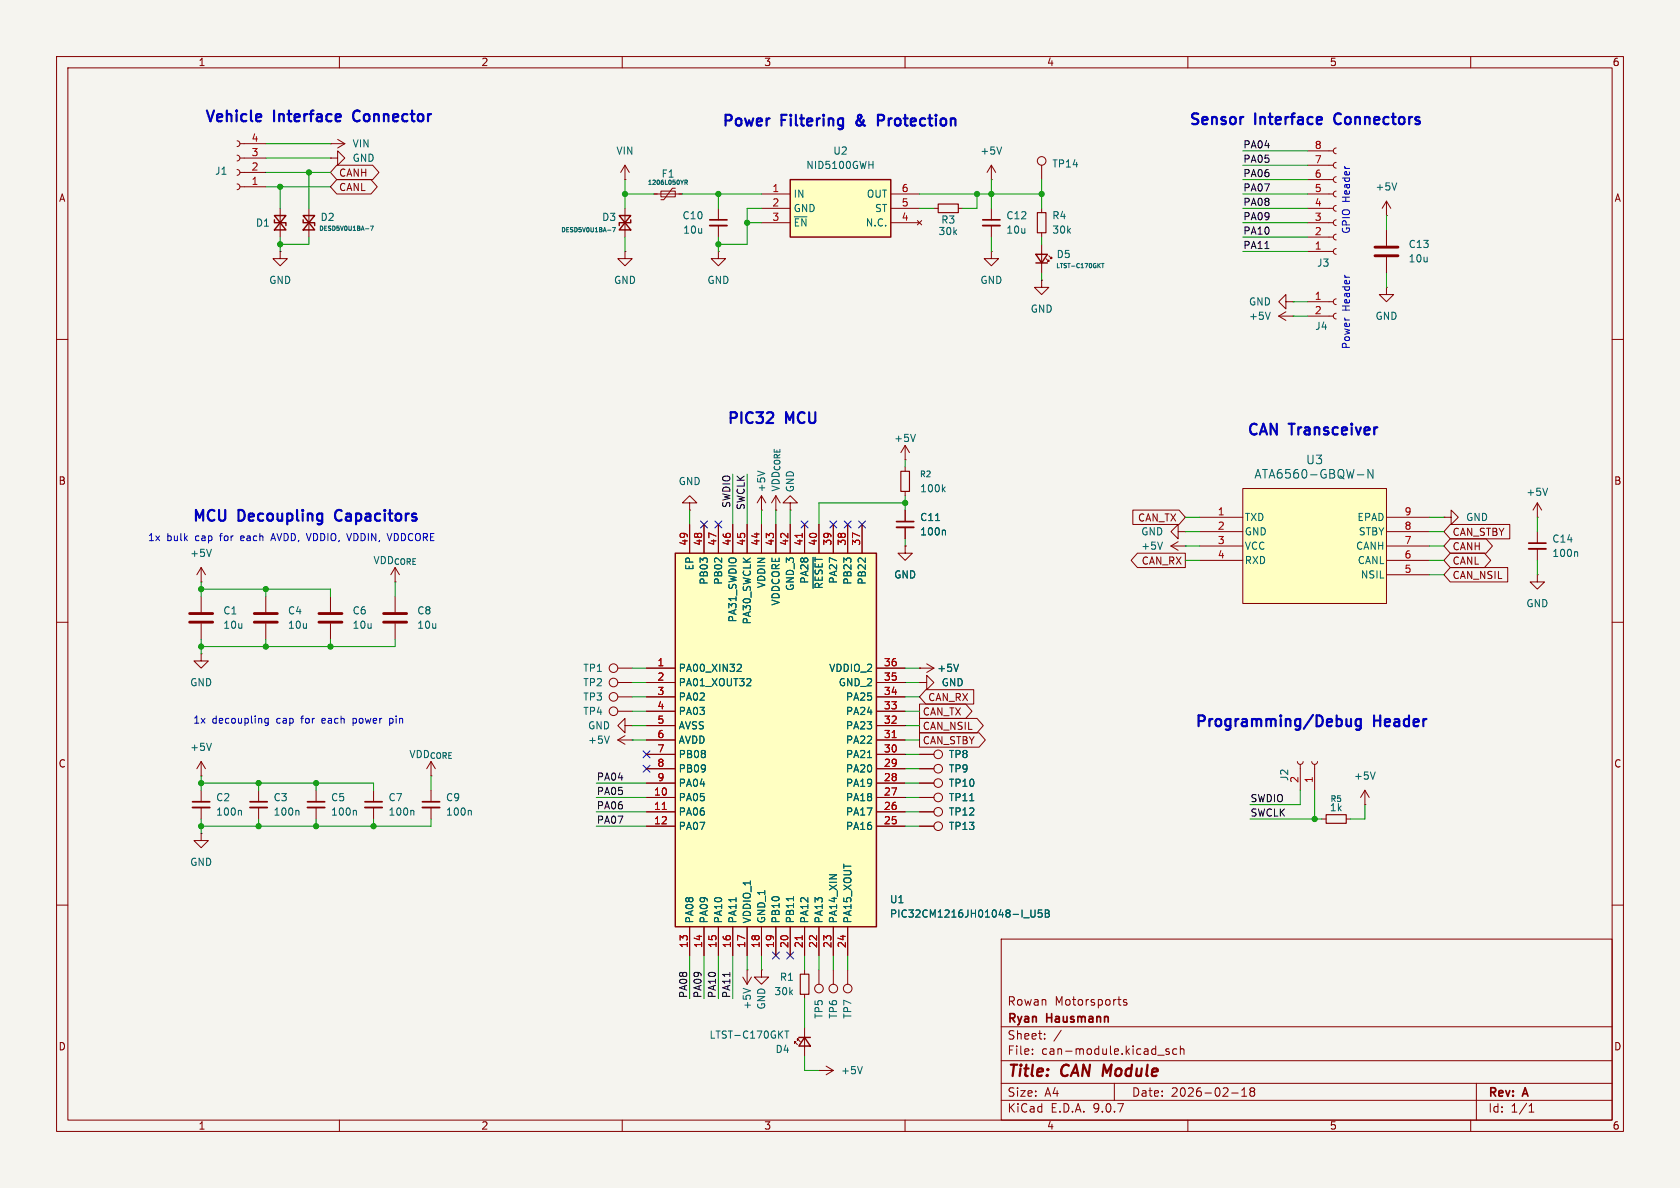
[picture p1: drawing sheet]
<svg xmlns="http://www.w3.org/2000/svg" width="297mm" height="210mm" viewBox="0 0 297 210" stroke-linecap="round" stroke-linejoin="round" font-family="sans-serif">
<defs><g id="words">
<g font-size="2.8" fill="#840000">
<text x="178" y="190.9">Title:</text>
<text x="187.7" y="190.9">CAN Module</text>
</g>
<g font-size="2.7" fill="#0000c2">
<text x="36" y="22.1">Vehicle</text>
<text x="48.4" y="22.1">Interface</text>
<text x="63.2" y="22.1">Connector</text>
<text x="127.4" y="22.9">Power</text>
<text x="138.1" y="22.9">Filtering</text>
<text x="152.1" y="22.9">&amp;</text>
<text x="156.7" y="22.9">Protection</text>
<text x="210" y="22.6">Sensor</text>
<text x="221.8" y="22.6">Interface</text>
<text x="236.7" y="22.6">Connectors</text>
<text x="128.3" y="75.4">PIC32</text>
<text x="138.9" y="75.4">MCU</text>
<text x="220.3" y="77.5">CAN</text>
<text x="228" y="77.5">Transceiver</text>
<text x="33.8" y="92.7">MCU</text>
<text x="42.1" y="92.7">Decoupling</text>
<text x="60" y="92.7">Capacitors</text>
<text x="211.1" y="129">Programming/Debug</text>
<text x="242.9" y="129">Header</text>
</g>
<g font-size="2.1" fill="#006464">
<text x="230.8" y="82.3">U3</text>
<text x="221.7" y="84.8">ATA6560-GBQW-N</text>
</g>
<g font-size="2.1" fill="#840000">
<text x="178" y="178">Rowan</text>
<text x="186.4" y="178">Motorsports</text>
<text x="178" y="184">Sheet:</text>
<text x="178" y="181.2">Ryan</text>
<text x="185.1" y="181.2">Hausmann</text>
<text x="178" y="186.7">File:</text>
<text x="184.1" y="186.7">can-module.kicad_sch</text>
<text x="178" y="196.9">KiCad</text>
<text x="178" y="194.1">Size:</text>
<text x="184.7" y="194.1">A4</text>
<text x="185.7" y="196.9">E.D.A.</text>
<text x="193.3" y="196.9">9.0.7</text>
<text x="200" y="194.1">Date:</text>
<text x="207" y="194.1">2026-02-18</text>
<text x="263" y="194.3">Rev:</text>
<text x="263" y="196.9">Id:</text>
<text x="267.1" y="196.9">1/1</text>
<text x="269.4" y="194.3">A</text>
</g>
<g font-size="1.8" fill="#840000">
<text x="35" y="11.9">1</text>
<text x="85" y="11.9">2</text>
<text x="135" y="11.9">3</text>
<text x="185" y="11.9">4</text>
<text x="235" y="11.9">5</text>
<text x="285" y="11.9">6</text>
<text x="10.3" y="35.9">A</text>
<text x="59.8" y="31.4">CANH</text>
<text x="59.8" y="34">CANL</text>
<text x="285.3" y="35.9">A</text>
<text x="10.3" y="85.9">B</text>
<text x="285.3" y="85.9">B</text>
<text x="201.1" y="92.4">CAN_TX</text>
<text x="256.7" y="94.9">CAN_STBY</text>
<text x="201.7" y="100">CAN_RX</text>
<text x="256.7" y="100">CANL</text>
<text x="256.7" y="97.5">CANH</text>
<text x="256.7" y="102.6">CAN_NSIL</text>
<text x="164" y="124.1">CAN_RX</text>
<text x="163" y="131.8">CAN_STBY</text>
<text x="163" y="129.2">CAN_NSIL</text>
<text x="163" y="126.7">CAN_TX</text>
<text x="10.3" y="135.9">C</text>
<text x="285.3" y="135.9">C</text>
<text x="10.3" y="185.9">D</text>
<text x="285.3" y="185.9">D</text>
<text x="35" y="199.9">1</text>
<text x="85" y="199.9">2</text>
<text x="135" y="199.9">3</text>
<text x="185" y="199.9">4</text>
<text x="235" y="199.9">5</text>
<text x="285" y="199.9">6</text>
</g>
<g font-size="1.8" fill="#a90000">
<text x="44.4" y="27.7">3</text>
<text x="44.4" y="25.1">4</text>
<text x="232.3" y="29">7</text>
<text x="232.3" y="26.4">8</text>
<text x="44.4" y="32.8">1</text>
<text x="44.4" y="30.2">2</text>
<text x="136.5" y="34">1</text>
<text x="159.3" y="34">6</text>
<text x="232.3" y="34">5</text>
<text x="232.3" y="31.5">6</text>
<text x="136.5" y="36.6">2</text>
<text x="136.5" y="39.1">3</text>
<text x="159.3" y="36.6">5</text>
<text x="159.3" y="39.1">4</text>
<text x="232.3" y="41.7">2</text>
<text x="232.3" y="39.1">3</text>
<text x="232.3" y="36.6">4</text>
<text x="232.3" y="44.2">1</text>
<text x="232.3" y="53.1">1</text>
<text x="232.3" y="55.6">2</text>
<text x="215.2" y="91.2">1</text>
<text x="215.2" y="93.7">2</text>
<text x="248.2" y="91.2">9</text>
<text x="248.2" y="93.7">8</text>
<text x="121.7" y="96.6" transform="rotate(-90 121.7 96.6)">49</text>
<text x="124.2" y="96.6" transform="rotate(-90 124.2 96.6)">48</text>
<text x="126.7" y="96.6" transform="rotate(-90 126.7 96.6)">47</text>
<text x="129.3" y="96.6" transform="rotate(-90 129.3 96.6)">46</text>
<text x="131.8" y="96.6" transform="rotate(-90 131.8 96.6)">45</text>
<text x="134.4" y="96.6" transform="rotate(-90 134.4 96.6)">44</text>
<text x="136.9" y="96.6" transform="rotate(-90 136.9 96.6)">43</text>
<text x="139.4" y="96.6" transform="rotate(-90 139.4 96.6)">42</text>
<text x="142" y="96.6" transform="rotate(-90 142 96.6)">41</text>
<text x="144.5" y="96.6" transform="rotate(-90 144.5 96.6)">40</text>
<text x="147.1" y="96.6" transform="rotate(-90 147.1 96.6)">39</text>
<text x="149.6" y="96.6" transform="rotate(-90 149.6 96.6)">38</text>
<text x="152.1" y="96.6" transform="rotate(-90 152.1 96.6)">37</text>
<text x="215.2" y="96.3">3</text>
<text x="215.2" y="98.8">4</text>
<text x="248.2" y="96.3">7</text>
<text x="248.2" y="98.8">6</text>
<text x="248.2" y="101.3">5</text>
<text x="116.1" y="117.9">1</text>
<text x="156.2" y="117.9">36</text>
<text x="116.1" y="120.4">2</text>
<text x="116.1" y="122.9">3</text>
<text x="116.1" y="125.5">4</text>
<text x="156.2" y="120.4">35</text>
<text x="156.2" y="122.9">34</text>
<text x="156.2" y="125.5">33</text>
<text x="116.1" y="128">5</text>
<text x="116.1" y="130.6">6</text>
<text x="156.2" y="128">32</text>
<text x="156.2" y="130.6">31</text>
<text x="116.1" y="133.1">7</text>
<text x="116.1" y="135.6">8</text>
<text x="156.2" y="133.1">30</text>
<text x="156.2" y="135.6">29</text>
<text x="115.5" y="140.7">10</text>
<text x="115.5" y="143.3">11</text>
<text x="116.1" y="138.2">9</text>
<text x="156.2" y="138.2">28</text>
<text x="156.2" y="140.7">27</text>
<text x="156.2" y="143.3">26</text>
<text x="229.6" y="138.5" transform="rotate(-90 229.6 138.5)">2</text>
<text x="232.2" y="138.5" transform="rotate(-90 232.2 138.5)">1</text>
<text x="115.5" y="145.8">12</text>
<text x="156.2" y="145.8">25</text>
<text x="121.7" y="167.7" transform="rotate(-90 121.7 167.7)">13</text>
<text x="124.2" y="167.7" transform="rotate(-90 124.2 167.7)">14</text>
<text x="126.7" y="167.7" transform="rotate(-90 126.7 167.7)">15</text>
<text x="129.3" y="167.7" transform="rotate(-90 129.3 167.7)">16</text>
<text x="131.8" y="167.7" transform="rotate(-90 131.8 167.7)">17</text>
<text x="134.4" y="167.7" transform="rotate(-90 134.4 167.7)">18</text>
<text x="136.9" y="167.7" transform="rotate(-90 136.9 167.7)">19</text>
<text x="139.4" y="167.7" transform="rotate(-90 139.4 167.7)">20</text>
<text x="142" y="167.7" transform="rotate(-90 142 167.7)">21</text>
<text x="144.5" y="167.7" transform="rotate(-90 144.5 167.7)">22</text>
<text x="147.1" y="167.7" transform="rotate(-90 147.1 167.7)">23</text>
<text x="149.6" y="167.7" transform="rotate(-90 149.6 167.7)">24</text>
</g>
<g font-size="1.8" fill="#006464">
<text x="62.2" y="26.3">VIN</text>
<text x="62.2" y="28.8">GND</text>
<text x="108.9" y="27.5">VIN</text>
<text x="147.2" y="27.5">U2</text>
<text x="173.2" y="27.5">+5V</text>
<text x="185.9" y="29.8">TP14</text>
<text x="37.9" y="31.1">J1</text>
<text x="116.9" y="31.6">F1</text>
<text x="140.2" y="35.2">IN</text>
<text x="142.4" y="30.1">NID5100GWH</text>
<text x="153.1" y="35.2">OUT</text>
<text x="243.1" y="33.9">+5V</text>
<text x="45.1" y="40.3">D1</text>
<text x="56.6" y="39.3">D2</text>
<text x="106.4" y="39.3">D3</text>
<text x="120.6" y="39">C10</text>
<text x="120.7" y="41.5">10u</text>
<text x="140.2" y="37.7">GND</text>
<text x="140.2" y="40.2">~{EN}</text>
<text x="153" y="40.2">N.C.</text>
<text x="154.6" y="37.7">ST</text>
<text x="165.8" y="41.8">30k</text>
<text x="166.3" y="39.7">R3</text>
<text x="177.8" y="39">C12</text>
<text x="177.8" y="41.5">10u</text>
<text x="185.9" y="39">R4</text>
<text x="185.9" y="41.5">30k</text>
<text x="186.7" y="45.8">D5</text>
<text x="232.7" y="47.3">J3</text>
<text x="248.9" y="44">C13</text>
<text x="248.9" y="46.6">10u</text>
<text x="47.5" y="50.4">GND</text>
<text x="108.5" y="50.4">GND</text>
<text x="125" y="50.4">GND</text>
<text x="173.2" y="50.4">GND</text>
<text x="182.1" y="55.5">GND</text>
<text x="220.7" y="54.2">GND</text>
<text x="220.7" y="56.7">+5V</text>
<text x="232.4" y="58.5">J4</text>
<text x="243.1" y="56.7">GND</text>
<text x="158" y="78.3">+5V</text>
<text x="119.9" y="86">GND</text>
<text x="135.5" y="87.1" transform="rotate(-90 135.5 87.1)">+5V</text>
<text x="138" y="87" transform="rotate(-90 138 87)">VDD_{CORE}</text>
<text x="140.6" y="87.1" transform="rotate(-90 140.6 87.1)">GND</text>
<text x="162.6" y="87.2">100k</text>
<text x="269.7" y="87.9">+5V</text>
<text x="162.6" y="94.8">100n</text>
<text x="162.6" y="92.3">C11</text>
<text x="201.7" y="94.8">GND</text>
<text x="220" y="92.3">TXD</text>
<text x="220" y="94.8">GND</text>
<text x="239.9" y="92.3">EPAD</text>
<text x="240.1" y="94.8">STBY</text>
<text x="259.1" y="92.3">GND</text>
<text x="33.5" y="98.7">+5V</text>
<text x="65.9" y="99.9">VDD_{CORE}</text>
<text x="122.8" y="100.9" transform="rotate(-90 122.8 100.9)">EP</text>
<text x="201.7" y="97.4">+5V</text>
<text x="220" y="97.4">VCC</text>
<text x="220" y="99.9">RXD</text>
<text x="239.6" y="97.4">CANH</text>
<text x="239.9" y="99.9">CANL</text>
<text x="274.3" y="98.7">100n</text>
<text x="274.3" y="96.1">C14</text>
<text x="125.3" y="103.5" transform="rotate(-90 125.3 103.5)">PB03</text>
<text x="127.9" y="103.5" transform="rotate(-90 127.9 103.5)">PB02</text>
<text x="135.5" y="104.1" transform="rotate(-90 135.5 104.1)">VDDIN</text>
<text x="138" y="107.1" transform="rotate(-90 138 107.1)">VDDCORE</text>
<text x="140.6" y="104.5" transform="rotate(-90 140.6 104.5)">GND_3</text>
<text x="143.1" y="103.3" transform="rotate(-90 143.1 103.3)">PA28</text>
<text x="145.6" y="104.2" transform="rotate(-90 145.6 104.2)">~{RESET}</text>
<text x="148.2" y="103.3" transform="rotate(-90 148.2 103.3)">PA27</text>
<text x="150.7" y="103.5" transform="rotate(-90 150.7 103.5)">PB23</text>
<text x="153.3" y="103.5" transform="rotate(-90 153.3 103.5)">PB22</text>
<text x="158" y="102.5">GND</text>
<text x="240.5" y="102.5">NSIL</text>
<text x="269.7" y="107.5">GND</text>
<text x="39.4" y="108.8">C1</text>
<text x="39.4" y="111.4">10u</text>
<text x="50.8" y="108.8">C4</text>
<text x="50.8" y="111.4">10u</text>
<text x="62.2" y="108.8">C6</text>
<text x="62.2" y="111.4">10u</text>
<text x="73.7" y="108.8">C8</text>
<text x="73.7" y="111.4">10u</text>
<text x="130.4" y="110.1" transform="rotate(-90 130.4 110.1)">PA31_SWDIO</text>
<text x="132.9" y="110.5" transform="rotate(-90 132.9 110.5)">PA30_SWCLK</text>
<text x="103" y="119">TP1</text>
<text x="119.9" y="119">PA00_XIN32</text>
<text x="146.5" y="119">VDDIO_2</text>
<text x="165.6" y="119">+5V</text>
<text x="33.5" y="121.5">GND</text>
<text x="103" y="121.5">TP2</text>
<text x="103" y="124.1">TP3</text>
<text x="119.9" y="121.5">PA01_XOUT32</text>
<text x="119.9" y="124.1">PA02</text>
<text x="148.2" y="121.5">GND_2</text>
<text x="149.5" y="124.1">PA25</text>
<text x="166.4" y="121.5">GND</text>
<text x="103" y="126.6">TP4</text>
<text x="103.9" y="129.1">GND</text>
<text x="103.9" y="131.7">+5V</text>
<text x="119.9" y="126.6">PA03</text>
<text x="119.9" y="129.1">AVSS</text>
<text x="119.9" y="131.7">AVDD</text>
<text x="149.5" y="126.6">PA24</text>
<text x="149.5" y="129.1">PA23</text>
<text x="149.5" y="131.7">PA22</text>
<text x="33.5" y="132.9">+5V</text>
<text x="72.3" y="134.2">VDD_{CORE}</text>
<text x="119.9" y="134.2">PB08</text>
<text x="119.9" y="136.8">PB09</text>
<text x="149.5" y="134.2">PA21</text>
<text x="149.5" y="136.8">PA20</text>
<text x="167.6" y="136.8">TP9</text>
<text x="167.6" y="134.2">TP8</text>
<text x="38.1" y="141.8">C2</text>
<text x="48.3" y="141.8">C3</text>
<text x="58.4" y="141.8">C5</text>
<text x="68.6" y="141.8">C7</text>
<text x="78.7" y="141.8">C9</text>
<text x="119.9" y="139.3">PA04</text>
<text x="119.9" y="141.8">PA05</text>
<text x="149.5" y="139.3">PA19</text>
<text x="149.5" y="141.8">PA18</text>
<text x="167.6" y="141.8">TP11</text>
<text x="167.6" y="139.3">TP10</text>
<text x="227.9" y="138.2" transform="rotate(-90 227.9 138.2)">J2</text>
<text x="235" y="143.6">1k</text>
<text x="239.3" y="138">+5V</text>
<text x="38.1" y="144.4">100n</text>
<text x="48.3" y="144.4">100n</text>
<text x="58.4" y="144.4">100n</text>
<text x="68.6" y="144.4">100n</text>
<text x="78.7" y="144.4">100n</text>
<text x="119.9" y="144.4">PA06</text>
<text x="119.9" y="146.9">PA07</text>
<text x="149.5" y="144.4">PA17</text>
<text x="149.5" y="146.9">PA16</text>
<text x="167.6" y="146.9">TP13</text>
<text x="167.6" y="144.4">TP12</text>
<text x="33.5" y="153.3">GND</text>
<text x="157.2" y="159.9">U1</text>
<text x="122.8" y="163.3" transform="rotate(-90 122.8 163.3)">PA08</text>
<text x="125.3" y="163.3" transform="rotate(-90 125.3 163.3)">PA09</text>
<text x="127.9" y="163.3" transform="rotate(-90 127.9 163.3)">PA10</text>
<text x="130.4" y="163.3" transform="rotate(-90 130.4 163.3)">PA11</text>
<text x="132.9" y="163.3" transform="rotate(-90 132.9 163.3)">VDDIO_1</text>
<text x="135.5" y="163.3" transform="rotate(-90 135.5 163.3)">GND_1</text>
<text x="138" y="163.3" transform="rotate(-90 138 163.3)">PB10</text>
<text x="140.6" y="163.3" transform="rotate(-90 140.6 163.3)">PB11</text>
<text x="143.1" y="163.3" transform="rotate(-90 143.1 163.3)">PA12</text>
<text x="145.6" y="163.3" transform="rotate(-90 145.6 163.3)">PA13</text>
<text x="148.2" y="163.3" transform="rotate(-90 148.2 163.3)">PA14_XIN</text>
<text x="150.7" y="163.3" transform="rotate(-90 150.7 163.3)">PA15_XOUT</text>
<text x="157.2" y="162.4">PIC32CM1216JH01048-I_U5B</text>
<text x="137.8" y="173.6">R1</text>
<text x="132.9" y="178.6" transform="rotate(-90 132.9 178.6)">+5V</text>
<text x="135.5" y="178.6" transform="rotate(-90 135.5 178.6)">GND</text>
<text x="136.8" y="176.1">30k</text>
<text x="125.3" y="183.8">LTST-C170GKT</text>
<text x="145.6" y="180.2" transform="rotate(-90 145.6 180.2)">TP5</text>
<text x="148.2" y="180.2" transform="rotate(-90 148.2 180.2)">TP6</text>
<text x="150.7" y="180.2" transform="rotate(-90 150.7 180.2)">TP7</text>
<text x="137" y="186.3">D4</text>
<text x="148.6" y="190.1">+5V</text>
</g>
<g font-size="1.8" fill="#0f0f0f">
<text x="219.7" y="26.3">PA04</text>
<text x="219.7" y="28.9">PA05</text>
<text x="219.7" y="31.4">PA06</text>
<text x="219.7" y="33.9">PA07</text>
<text x="219.7" y="41.6">PA10</text>
<text x="219.7" y="39">PA09</text>
<text x="219.7" y="36.5">PA08</text>
<text x="219.7" y="44.1">PA11</text>
<text x="129.2" y="89.9" transform="rotate(-90 129.2 89.9)">SWDIO</text>
<text x="131.7" y="90.3" transform="rotate(-90 131.7 90.3)">SWCLK</text>
<text x="105.4" y="140.6">PA05</text>
<text x="105.4" y="138.1">PA04</text>
<text x="105.4" y="143.2">PA06</text>
<text x="221" y="141.9">SWDIO</text>
<text x="105.4" y="145.7">PA07</text>
<text x="221" y="144.4">SWCLK</text>
<text x="121.6" y="176.5" transform="rotate(-90 121.6 176.5)">PA08</text>
<text x="124.1" y="176.5" transform="rotate(-90 124.1 176.5)">PA09</text>
<text x="126.7" y="176.5" transform="rotate(-90 126.7 176.5)">PA10</text>
<text x="129.2" y="176.5" transform="rotate(-90 129.2 176.5)">PA11</text>
</g>
<g font-size="1.8" fill="#0000c2">
<text x="238.9" y="35.8" transform="rotate(-90 238.9 35.8)">Header</text>
<text x="238.9" y="41.4" transform="rotate(-90 238.9 41.4)">GPIO</text>
<text x="238.9" y="55" transform="rotate(-90 238.9 55)">Header</text>
<text x="238.9" y="61.8" transform="rotate(-90 238.9 61.8)">Power</text>
<text x="26.1" y="95.9">1x</text>
<text x="29.5" y="95.9">bulk</text>
<text x="34.6" y="95.9">cap</text>
<text x="39.2" y="95.9">for</text>
<text x="43" y="95.9">each</text>
<text x="48.7" y="95.9">AVDD, VDDIO,</text>
<text x="62.5" y="95.9">VDDIN,</text>
<text x="69.8" y="95.9">VDDCORE</text>
<text x="34.1" y="128.1">1x</text>
<text x="37.5" y="128.1">decoupling</text>
<text x="49" y="128.1">cap</text>
<text x="53.6" y="128.1">for</text>
<text x="57.4" y="128.1">each</text>
<text x="63" y="128.1">power</text>
<text x="69.7" y="128.1">pin</text>
</g>
<g font-size="1.4" fill="#006464">
<text x="162.5" y="84.6">R2</text>
<text x="235.1" y="142">R5</text>
</g>
<g font-size="1.1" fill="#006464">
<text x="114.4" y="32.9">1206L050YR</text>
<text x="56.3" y="41">DESD5V0U1BA-7</text>
<text x="99.1" y="41.2">DESD5V0U1BA-7</text>
<text x="186.6" y="47.6">LTST-C170GKT</text>
</g>
</g></defs>
<path d="M0 0h297v210h-297z" fill="#f5f4ef" stroke="#f5f4ef" stroke-width=".18"/>
<g fill="none" stroke="#840000" stroke-width=".18">
<path d="M10 10h277v190h-277zM12 12h273v186h-273zM60 10v2M110 10v2M160 10v2M210 10v2M260 10v2M110.5 31.8h.1M110.5 29.2l-.8 1.3M110.5 29.2l.8 1.3M110.5 29.2v2.6M110.5 36.8v5.1"/>
<path d="M10 60h2M285 60h2M160 96.5v1.3h1.3l-1.3 1.3-1.3-1.3h1.3M160 96.5h.1M10 110h2M35.6 115.6v1.2h1.2l-1.2 1.3-1.3-1.3h1.3M35.6 115.6h.1M35.6 105.4v2.8M35.6 110.2v2.8M47 105.4v2.8M47 110.2v2.8M58.4 105.4v2.8"/>
<path d="M58.4 110.2v2.8M69.8 105.4v2.8M69.8 110.2v2.8M162.6 118.1h.1M162.6 118.1h2.5M163.8 117.3l1.3 .8M165.1 118.1l-1.3 .8M285 110h2M35.6 137.2h.1M35.6 134.6v2.6M35.6 134.6l-.8 1.3M35.6 134.6l.7 1.3"/>
<path d="M66 139.7v2M76.2 137.2h.1M76.2 134.6v2.6M76.2 139.7v2M76.2 134.6l-.8 1.3M76.2 134.6l.8 1.3M162.6 120.7h1.2v-1.3l1.3 1.3-1.3 1.2v-1.2M162.6 120.7h.1M162.6 138.4h2.5M162.6 135.9h2.5M66 142.7v2.1M76.2 142.7v2.1"/>
<path d="M162.6 141h2.5M10 160h2M177 166h108v32h-108zM197.6 176.7h.6M198 177.7h.2M199.2 176.8l-.4-.1-.2 .2 .1 .2 .5 .2v.3h-.6M285 160h2M60 198v2M110 198v2M160 198v2M177 194.5h108M177 191.5h108"/>
<path d="M177 187.5h108M177 181.5h108M182.5 186.3v.1M182.5 185.5v.1M184.7 183.6v.1M184.7 182.8v.1M187.6 182.1l-1.3 2M197 191.5v3M204.7 186.5h1.1M206.7 185.5l-.4-.1-.2 .2 .1 .2 .5 .2v.3h-.6M208 185.5l-.4-.1-.3 .3v.4l.2 .2h.5M208.7 185.5l.2-.1 .3 .1 .1 .9"/>
<path d="M208.7 184.9v1.5M210 198v2M217.7 193.2h1.2M219.5 193.8h.9M219.5 192.7l.5-.4v1.5M221.2 192.9l-.2 .3v.5l.2 .1 .5-.1 .1-.2-.1-.4-.2-.2M221.2 192.9l-.2-.2 .2-.4 .5 .1 .1 .2-.3 .3M221.2 192.9h.3M260 198v2M261 191.5v6.5M270.3 196.6h.9M270.3 195.5l.4-.4v1.5"/>
<circle cx="165.9" cy="135.9" r=".76"/>
<circle cx="165.9" cy="138.4" r=".76"/>
<circle cx="165.9" cy="141" r=".76"/>
</g>
<path d="M33.5 108.5h4.1M33.5 110h4.1M45 108.5h4M45 110h4M56.4 108.5h4.1M56.4 110h4.1M67.8 108.5h4.1M67.8 110h4.1" fill="none" stroke="#840000" stroke-width=".51"/>
<path d="M107.4 40.7h.6M108.3 40.2h.5l-.3 .8M169.5 117.4l-.5 1.3M37.4 131.4l-.4 1.3M73 143.2l.2 .2v.7M83.1 143.2l.2 .2v.7M171.4 141.5h.8" fill="none" stroke="#006464" stroke-width=".18"/>
<path d="M64.5 141.7h3.1M74.7 141.7h3" fill="none" stroke="#840000" stroke-width=".3"/>
<path d="M64.5 142.7h3.1M74.7 142.7h3" fill="none" stroke="#840000" stroke-width=".33"/>
<path d="M109.5 38.1l2 2.5h-2l2-2.5zM111.5 38.9v.5h-2v.5" fill="none" stroke="#840000" stroke-width=".25"/>
<path d="M219.7 86.4h25.4v20.3h-25.4z" fill="#ffffc2"/>
<g fill="none" stroke="#840000" stroke-width=".18">
<path d="M110.5 44.5v1.2h1.3l-1.3 1.3-1.3-1.3h1.3M110.5 44.5h.1M160 78.7v2.6M160 78.7l-.7 1.3M160 78.7l.8 1.3M160 81.3h.1M160 82.6v.7M160 86.9v.7M160 90.2v2M160 93.2v2.1M207 96.5h2.5M207 96.5l1.3 .8"/>
<path d="M208.3 94v-1.3l-1.3 1.3 1.3 1.3v-1.3h1.2M208.3 95.8l-1.3 .7M209.5 96.5h.1M209.5 94h.1M212.1 91.4h7.6M212.1 94h7.6M212.1 96.5h7.6M212.1 99.1h7.6M219.7 86.4h25.4v20.3h-25.4zM245.1 91.4h7.6M245.1 94h7.6M245.1 96.5h7.6"/>
<path d="M245.1 99.1h7.6M255.3 91.4h1.2v-1.2l1.3 1.2-1.3 1.3v-1.3M255.3 91.4h.1M271.8 91.4h.1M271.8 88.9l-.8 1.3M271.8 88.9l.7 1.3M271.8 88.9v2.5M271.8 94v2M271.8 97v2.1M245.1 101.6h7.6M271.8 101.6v1.3h1.2l-1.2 1.2-1.3-1.2h1.3M271.8 101.6h.1"/>
<path d="M229.4 134.6l.1 .4 .4 .1 .3-.1 .2-.4M229.9 135.1v4.6M231.9 134.6l.2 .4 .3 .1 .4-.1 .1-.4M232.4 135.1v4.6M241.3 139.7l-.8 1.3M241.3 139.7l.8 1.3M241.3 139.7v2.5M162.6 146.1h2.5M162.6 143.5h2.5M233.7 144.8h.7M238 144.8h.8M241.3 142.2h.1"/>
<circle cx="165.9" cy="143.5" r=".76"/>
<circle cx="165.9" cy="146" r=".76"/>
</g>
<path d="M161.8 76.8l-.4 1.2M165.4 92h.7M166.7 86.5l.4 .4M167 93.7l.1 .2v.7M167.1 86.1l-.5 .5M205.5 95.8l-.4 1.3M240 83.9h1.1M242.7 83v1.5l-.9-1.5v1.5M273.6 86.3l-.4 1.3M278.7 97.5l.2 .2v.7M243.1 136.5l-.4 1.2" fill="none" stroke="#006464" stroke-width=".18"/>
<path d="M158.5 92.2h3M270.3 96h3" fill="none" stroke="#840000" stroke-width=".3"/>
<path d="M158.5 93.2h3M270.3 97h3" fill="none" stroke="#840000" stroke-width=".33"/>
<path d="M159.3 83.3h1.5v3.6h-1.5zM234.4 144h3.6v1.5h-3.6z" fill="none" stroke="#840000" stroke-width=".2"/>
<path d="M119.4 97.8h35.5v66h-35.5z" fill="#ffffc2"/>
<path d="M48.5 38.1h2l-2 2.5h2zM48.5 38.9v.5h2v.5M53.6 38.1h2l-2 2.5h2zM53.6 38.9v.5h2v.5M119.4 97.8h35.5v66h-35.5zM141.2 183.4h2.1M142.2 183.4l1.1 1.5h-2.1z" fill="none" stroke="#840000" stroke-width=".25"/>
<g fill="none" stroke="#840000" stroke-width=".18">
<path d="M41.9 32.5l.4 .2 .1 .3-.1 .4-.4 .1M41.9 30l.4 .1 .1 .4-.1 .3-.4 .2M41.9 27.4l.4 .2 .1 .3-.1 .4-.4 .1M41.9 24.9l.4 .1 .1 .4-.1 .4-.4 .1M42.4 25.4h4.6M42.4 33h4.6M42.4 30.5h4.6M42.4 27.9h4.6M49.5 36.8v5.1M54.6 36.8v5.1M58.4 25.4h.1M58.4 27.9h1.3v-1.2l1.3 1.2-1.3 1.3v-1.3"/>
<path d="M58.4 27.9h.1M58.4 25.4h2.6M59.7 24.6l1.3 .8M61 25.4l-1.3 .8M115.6 34.3h5M116.8 33.8h2.6v1h-2.6zM119.4 33.3h-.5l-1.6 2h-.5M127 36.8v2.1M127 39.9v2M184.1 29.2v2.6M245.1 38.1h.1M245.1 35.6l-.8 1.2"/>
<path d="M245.1 35.6l.8 1.2M245.1 35.6v2.5M49.5 44.5v1.2h1.3l-1.3 1.3-1.2-1.3h1.2M49.5 44.5h.1M127 44.5v1.2h1.3l-1.3 1.3-1.3-1.3h1.3M127 44.5h.1M121.9 88.9h1.3l-1.3-1.3-1.3 1.3h1.3v1.3M121.9 90.2h.1M121.9 92.7v5.1M124.5 92.7v5.1M127 92.7v5.1M129.5 92.7v5.1"/>
<path d="M132.1 92.7v5.1M134.6 90.2h.1M134.6 87.6v2.6M134.6 92.7v5.1M134.6 87.6l-.7 1.3M134.6 87.6l.8 1.3M137.2 90.2h.1M137.2 87.6v2.6M137.2 92.7v5.1M137.2 87.6l-.8 1.3M137.2 87.6l.7 1.3M139.7 88.9h1.3l-1.3-1.3-1.3 1.3h1.3v1.3"/>
<path d="M139.7 90.2h.1M139.7 92.7v5.1M142.2 92.7v5.1M144.8 92.7v5.1M147.3 92.7v5.1M149.9 92.7v5.1M152.4 92.7v5.1M35.6 102.9h.1M35.6 100.3l-.8 1.3M35.6 100.3l.7 1.3M35.6 100.3v2.6M69.8 102.9h.1"/>
<path d="M69.8 100.3l-.7 1.3M69.8 100.3l.8 1.3M69.8 100.3v2.6M109.2 118.1h2.6M114.3 118.1h5.1M154.9 118.1h5.1M35.6 139.7v2M45.7 139.7v2M55.9 139.7v2M109.2 120.7h2.6M109.2 123.2h2.6M109.2 125.7h2.6"/>
<path d="M109.2 130.8h2.6M109.2 130.8l1.3 .8M110.5 128.3v-1.3l-1.3 1.3 1.3 1.2v-1.2h1.3M110.5 130l-1.3 .8M111.8 128.3h.1M111.8 130.8h.1M114.3 120.7h5.1M114.3 123.2h5.1M114.3 125.7h5.1M114.3 128.3h5.1M114.3 130.8h5.1M114.3 133.4h5.1"/>
<path d="M114.3 135.9h5.1M114.3 138.4h5.1M154.9 120.7h5.1M154.9 123.2h5.1M154.9 125.7h5.1M154.9 128.3h5.1M154.9 130.8h5.1M154.9 133.4h5.1M154.9 135.9h5.1M154.9 138.4h5.1M162.6 133.4h2.5M35.6 147.3v1.3h1.2l-1.2 1.3-1.3-1.3h1.3"/>
<path d="M35.6 147.3h.1M35.6 142.7v2.1M45.7 142.7v2.1M55.9 142.7v2.1M114.3 141h5.1M114.3 143.5h5.1M114.3 146.1h5.1M154.9 141h5.1M154.9 143.5h5.1M154.9 146.1h5.1M121.9 163.8v5.1M124.5 163.8v5.1"/>
<path d="M127 163.8v5.1M129.5 163.8v5.1M131.3 172.7l.8 1.3M132.1 171.5h.1M132.1 163.8v5.1M132.1 171.5v2.5M132.8 172.7l-.7 1.3M134.6 171.5v1.2h1.3l-1.3 1.3-1.3-1.3h1.3M134.6 171.5h.1M134.6 163.8v5.1M137.2 163.8v5.1M139.7 163.8v5.1"/>
<path d="M142.2 163.8v5.1M142.2 171.5v.7M142.2 175.8v.7M144.8 163.8v5.1M144.8 171.5v2.5M147.3 163.8v5.1M147.3 171.5v2.5M149.9 163.8v5.1M149.9 171.5v2.5M140.7 184.2h-.2v.2v-.2l.5 .5M141.2 183.6h-.2v.3v-.3l.5 .6M142.2 181.6v5.1"/>
<path d="M144.8 189.2h.1M144.8 189.2h2.5M146 188.5l1.3 .7M147.3 189.2l-1.3 .8"/>
<circle cx="184.1" cy="28.4" r=".76"/>
<circle cx="108.5" cy="118.1" r=".76"/>
<circle cx="108.5" cy="120.6" r=".76"/>
<circle cx="108.5" cy="125.7" r=".76"/>
<circle cx="108.5" cy="123.2" r=".76"/>
<circle cx="165.9" cy="133.3" r=".76"/>
<circle cx="144.8" cy="174.8" r=".76"/>
<circle cx="147.3" cy="174.8" r=".76"/>
<circle cx="149.9" cy="174.8" r=".76"/>
</g>
<g fill="none" stroke="#006464" stroke-width=".18">
<path d="M65.5 40h.5l-.3 .7M121.1 32.2h.3l.1-.3-.4-.1v.8M121.3 32.2l.2 .4M246.9 32.3l-.4 1.3M64.6 40.4h.6M37.4 97.1l-.4 1.3M133.9 83.3l1.3 .4M143.7 98.5v5.5M130.5 117.4l.4 .1 .2 .3-.8 .9h.8M132.5 120l.2 .2v.3l-.7 .7h.7M107.7 130.1l-.4 1.3M153.4 133.9h.7"/>
<path d="M42.5 143.2l.2 .2v.7M52.7 143.2l.1 .2v.7M62.8 143.2l.2 .2v.7M130.1 158.7v.7M140.3 158.5v.7M131.4 174.7l1.3 .4M182.3 160.9v1l.2 .2h.4l.1-.2v-1M184.2 160.9h-.6l-.1 .6 .2-.2 .4 .1 .1 .2v.4l-.2 .1-.5-.1M184.8 160.9h.4l.3 .2-.3 .4 .3 .1v.3l-.2 .2h-.5zM184.8 161.5h.4M138.7 182.3h.8M139.1 182.3v1.2"/>
<path d="M152.5 188.5l-.5 1.3"/>
</g>
<path d="M141.8 94.3v.7M157.7 130.4h.7M117.1 143.1h.7M141.8 165.4v.7" fill="none" stroke="#a90000" stroke-width=".18"/>
<path d="M141.5 172.2h1.5v3.6h-1.5z" fill="none" stroke="#840000" stroke-width=".2"/>
<path d="M125.5 38.9h3M34 141.7h3.1M44.2 141.7h3M54.4 141.7h3" fill="none" stroke="#840000" stroke-width=".3"/>
<path d="M125.5 39.9h3M34 142.7h3.1M44.2 142.7h3M54.4 142.7h3" fill="none" stroke="#840000" stroke-width=".33"/>
<path d="M139.7 31.8h17.8v10.1h-17.8z" fill="#ffffc2"/>
<path d="M139.7 31.8h17.8v10.1h-17.8zM183.1 45h2.1l-1.1 1.5zM183.1 46.5h2.1" fill="none" stroke="#840000" stroke-width=".25"/>
<g fill="none" stroke="#840000" stroke-width=".18">
<path d="M59.5 29.2h6.4l1.1 1.3-1.1 1.3h-6.4l-1.1-1.3zM59.5 31.7h6.1l1.1 1.3-1.1 1.3h-6.1l-1.1-1.3zM134.6 34.3h5.1M134.6 36.8h5.1M134.6 39.4h5.1M157.5 34.3h5.1M157.5 36.8h5.1M157.5 39.4h5.1M162.2 39l.7 .8M162.9 39l-.7 .8M165.1 36.8h.8M169.4 36.8h.8"/>
<path d="M175.3 31.8h.1M175.3 29.2l-.8 1.3M175.3 29.2l.7 1.3M175.3 29.2v2.6M175.3 36.8v2.1M175.3 39.9v2M184.1 36.8v.8M231.1 34.3h4.6M231.1 36.8h4.6M231.1 39.4h4.6M231.1 31.8h4.6M231.1 29.2h4.6"/>
<path d="M231.1 26.7h4.6M236.2 38.9l-.3 .1-.2 .4 .2 .3 .3 .2M236.2 36.3l-.3 .2-.2 .3 .2 .4 .3 .1M236.2 33.8l-.3 .1-.2 .4 .2 .3 .3 .2M236.2 31.2l-.3 .2-.2 .4 .2 .3 .3 .2M236.2 28.7l-.3 .2-.2 .3 .2 .4 .3 .1M236.2 26.2l-.3 .1-.2 .4 .2 .3 .3 .2M175.3 44.5v1.2h1.2l-1.2 1.3-1.3-1.3h1.3M175.3 44.5h.1M184.1 49.5v1.3h1.3l-1.3 1.3-1.2-1.3h1.2M184.1 49.5h.1M184.1 41.1v.8"/>
<path d="M184.1 43.2v5.1M184.9 45.7l.5 .5v-.2v.2h-.2M185.4 45.2l.5 .5v-.2v.2h-.2M226.1 55.9h2.5M226.1 55.9l1.2 .7M227.3 53.3v-1.2l-1.2 1.2 1.2 1.3v-1.3h1.3M227.3 55.1l-1.2 .8M228.6 53.3h.1M228.6 55.9h.1M231.1 44.5h4.6M231.1 41.9h4.6M231.1 53.3h4.6"/>
<path d="M231.1 55.9h4.6M236.2 43.9l-.3 .2-.2 .4 .2 .3 .3 .2M236.2 41.4l-.3 .2-.2 .3 .2 .4 .3 .1M236.2 52.8l-.3 .2-.2 .3 .2 .4 .3 .1M236.2 55.4l-.3 .1-.2 .4 .2 .3 .3 .2M245.1 50.8v1.3h1.3l-1.3 1.2-1.3-1.2h1.3M245.1 50.8h.1M245.1 40.6v2.8M245.1 45.5v2.8M121.9 92.7v5.1M124.5 92.7v5.1M127 92.7v5.1"/>
<path d="M129.5 92.7v5.1M132.1 92.7v5.1M134.6 92.7v5.1M137.2 92.7v5.1M139.7 92.7v5.1M142.2 92.7v5.1M144.8 92.7v5.1M147.3 92.7v5.1M149.9 92.7v5.1M152.4 92.7v5.1M160 96.5h.1M160 90.2v2"/>
<path d="M160 93.2v2.1M200.3 90.2h8.1l1.1 1.2-1.1 1.3h-8.1zM201.1 97.8h8.4v2.5h-8.4l-1.1-1.2zM256.4 97.8h6l1.1 1.3-1.1 1.2h-6l-1.1-1.2zM256.4 95.2h6.3l1.1 1.3-1.1 1.3h-6.3l-1.1-1.3zM256.4 92.7h10.5v2.6h-10.5l-1.1-1.3zM114.3 118.1h5.1M154.9 118.1h5.1M162.6 118.1h.1M256.4 100.3h10.1v2.6h-10.1l-1.1-1.3zM114.3 120.7h5.1M114.3 123.2h5.1"/>
<path d="M114.3 125.7h5.1M114.3 128.3h5.1M114.3 130.8h5.1M114.3 133.4h5.1M114.3 135.9h5.1M114.3 138.4h5.1M154.9 120.7h5.1M154.9 123.2h5.1M154.9 125.7h5.1M154.9 128.3h5.1M154.9 130.8h5.1M154.9 133.4h5.1"/>
<path d="M154.9 135.9h5.1M154.9 138.4h5.1M162.6 129.5h10.5l1.1 1.3-1.1 1.3h-10.5zM162.6 127h10.1l1.1 1.3-1.1 1.2h-10.1zM162.6 124.5h8.1l1.1 1.2-1.1 1.3h-8.1zM162.6 120.7h.1M162.6 133.4h2.5M162.6 135.9h2.5M162.6 138.4h2.5M163.7 121.9h8.4v2.6h-8.4l-1.1-1.3zM114.3 146.1h5.1M114.3 143.5h5.1"/>
<path d="M114.3 141h5.1M154.9 146.1h5.1M154.9 143.5h5.1M154.9 141h5.1M162.6 146.1h2.5M162.6 143.5h2.5M162.6 141h2.5M121.9 163.8v5.1M124.5 163.8v5.1M127 163.8v5.1M129.5 163.8v5.1M132.1 163.8v5.1"/>
<path d="M134.6 163.8v5.1M137.2 163.8v5.1M139.7 163.8v5.1M142.2 163.8v5.1M144.8 163.8v5.1M147.3 163.8v5.1M149.9 163.8v5.1"/>
</g>
<g fill="none" stroke="#006464" stroke-width=".18">
<path d="M153.6 29.1h.7M154.3 28.5v1.3M177.1 26l-.4 1.2M194.7 46.6h.5M195 46.6v.7M224.6 55.2l-.5 1.3M143.7 98.5v5.5M165.4 92h.7M167 93.7l.1 .2v.7M130.5 117.4l.4 .1 .2 .3-.8 .9h.8M132.5 120l.2 .2v.3l-.7 .7h.7M169.5 117.4l-.5 1.3"/>
<path d="M153.4 133.9h.7M130.1 158.7v.7M140.3 158.5v.7M171.4 141.5h.8M182.3 160.9v1l.2 .2h.4l.1-.2v-1M184.2 160.9h-.6l-.1 .6 .2-.2 .4 .1 .1 .2v.4l-.2 .1-.5-.1M184.8 160.9h.4l.3 .2-.3 .4 .3 .1v.3l-.2 .2h-.5zM184.8 161.5h.4"/>
</g>
<path d="M243.1 43.7h4M243.1 45.2h4" fill="none" stroke="#840000" stroke-width=".51"/>
<path d="M165.9 36.1h3.5v1.5h-3.5zM183.4 37.6h1.5v3.5h-1.5z" fill="none" stroke="#840000" stroke-width=".2"/>
<path d="M173.7 38.9h3.1" fill="none" stroke="#840000" stroke-width=".3"/>
<path d="M173.7 39.9h3.1" fill="none" stroke="#840000" stroke-width=".33"/>
<path d="M223.6 43.9h.7M129 171.9v.7" fill="none" stroke="#0f0f0f" stroke-width=".18"/>
<g fill="none" stroke="#009600" stroke-width=".18">
<path d="M47 25.4h11.4M47 30.5h11.4M47 27.9h11.4M47 33h11.4M49.5 33v3.8M54.6 30.5v6.3M110.5 34.3h5.1M110.5 31.8v5M120.6 34.3h14M127 34.3v2.5M132.1 39.4h2.5M134.6 36.8h-2.5v6.4h-5.1"/>
<path d="M162.6 34.3h21.5M162.6 36.8h2.5M172.7 34.3v2.5h-2.5M175.3 31.8v5M184.1 31.8v5M219.7 34.3h11.4M219.7 36.8h11.4M219.7 39.4h11.4M219.7 31.8h11.4M219.7 29.2h11.4M219.7 26.7h11.4M245.1 38.1v2.5"/>
<path d="M49.5 41.9v2.6M54.6 41.9v1.3h-5.1M110.5 41.9v2.6M127 41.9v2.6M175.3 41.9v2.6M184.1 41.9v1.3M184.1 48.3v1.2M219.7 41.9h11.4M219.7 44.5h11.4M228.6 55.9h2.5M228.6 53.3h2.5M245.1 48.3v2.5"/>
<path d="M121.9 90.2v2.5M129.5 83.8v8.9M132.1 83.8v8.9M134.6 90.2v2.5M137.2 90.2v2.5M139.7 90.2v2.5M160 88.9h-15.2v3.8M160 81.3v1.3M160 87.6v2.6M160 95.3v1.2M209.5 99.1h2.6M209.5 96.5h2.6"/>
<path d="M209.5 94h2.6M209.5 91.4h2.6M252.7 99.1h2.6M252.7 96.5h2.6M252.7 94h2.6M252.7 91.4h2.6M271.8 91.4v2.6M271.8 99.1v2.5M35.6 102.9v2.5M35.6 113v2.6M35.6 104.1h22.8v1.3M47 104.1v1.3"/>
<path d="M47 113v1.3M58.4 113v1.3M69.8 102.9v2.5M69.8 113v1.3h-34.2M111.8 118.1h2.5M160 118.1h2.6M252.7 101.6h2.6M35.6 137.2v2.5M35.6 138.4h30.4v1.3M45.7 138.4v1.3M55.9 138.4v1.3M76.2 137.2v2.5"/>
<path d="M105.4 138.4h8.9M111.8 130.8h2.5M111.8 123.2h2.5M111.8 120.7h2.5M111.8 128.3h2.5M111.8 125.7h2.5M160 138.4h2.6M160 130.8h2.6M160 123.2h2.6M160 120.7h2.6M160 128.3h2.6M160 125.7h2.6"/>
<path d="M160 133.4h2.6M160 135.9h2.6M229.9 139.7v2.5h-8.9M232.4 139.7v5.1M35.6 144.8v2.5M45.7 144.8v1.3M55.9 144.8v1.3M66 144.8v1.3M76.2 144.8v1.3h-40.6M105.4 143.5h8.9M105.4 146.1h8.9M105.4 141h8.9"/>
<path d="M160 143.5h2.6M160 146.1h2.6M160 141h2.6M221 144.8h12.7M241.3 142.2v2.6h-2.5M121.9 168.9v7.6M124.5 168.9v7.6M127 168.9v7.6M129.5 168.9v7.6M132.1 168.9v2.6M134.6 168.9v2.6M142.2 168.9v2.6"/>
<path d="M142.2 176.5v5.1M144.8 168.9v2.6M147.3 168.9v2.6M149.9 168.9v2.6M142.2 186.7v2.5h2.6"/>
</g>
<g fill="none" stroke="#000084" stroke-width=".18">
<path d="M123.9 92.1l1.2 1.2M125.1 92.1l-1.2 1.2M126.4 92.1l1.2 1.2M127.6 92.1l-1.2 1.2M141.6 92.1l1.2 1.2M142.8 92.1l-1.2 1.2M146.7 92.1l1.2 1.2M147.9 92.1l-1.2 1.2M149.3 92.1l1.2 1.2M150.5 92.1l-1.2 1.2M151.8 92.1l1.2 1.2M153 92.1l-1.2 1.2"/>
<path d="M113.7 132.7l1.2 1.3M113.7 135.3l1.2 1.2M114.9 132.7l-1.2 1.3M114.9 135.3l-1.2 1.2M136.6 168.3l1.2 1.2M137.8 168.3l-1.2 1.2M139.1 168.3l1.2 1.2M140.3 168.3l-1.2 1.2"/>
</g>
<path d="M46.1 20.3l.1 .3-.9 .2M155.2 21.3h.7M155.9 20.3h-.7v1.9M136.3 72.9l.2 .1a.52 .52 0 0 1 .1 .7l-1.1 1.1h1.2M238 128.1l.1 .2a.52 .52 0 0 0 .7-.1M238.8 127.1v1.3M240.6 127.2l-.6-.1-.3 .4v.5l.1 .3 .2 .1 .6-.1M240.6 127.1v1.5a.52 .52 0 0 1-.9 .3" fill="none" stroke="#0000c2" stroke-width=".38"/>
<path d="M48 95.2h.6M48.3 94.3l-.4 1.3M61.3 94.3l.4 1.3 .4-1.3M69.3 94.3l-.4 1.3M47.4 127v1l-.2 .3-.3-.1M47.4 127.1l-.3-.1-.3 .2 .1 .6h.5M62.4 127v1.3M62.4 127.8h.1M62.5 127l-.1 .1M68.9 127.8h.4M68.9 127v1.3M69.3 127l-.4 .1" fill="none" stroke="#0000c2" stroke-width=".18"/>
<path d="M141.8 94.3v.7M157.7 130.4h.7M117.1 143.1h.7M141.8 165.4v.7" fill="none" stroke="#a90000" stroke-width=".18"/>
<g fill="#009600" stroke="#009600" stroke-width=".18">
<circle cx="127" cy="34.3" r=".46"/>
<circle cx="172.7" cy="34.3" r=".46"/>
<circle cx="184.1" cy="34.3" r=".46"/>
<circle cx="175.3" cy="34.3" r=".46"/>
<circle cx="232.4" cy="144.8" r=".46"/>
<circle cx="160" cy="88.9" r=".46"/>
<circle cx="47" cy="114.3" r=".46"/>
<circle cx="35.6" cy="114.3" r=".46"/>
<circle cx="58.4" cy="114.3" r=".46"/>
<circle cx="110.5" cy="34.3" r=".46"/>
<circle cx="132.1" cy="39.4" r=".46"/>
<circle cx="127" cy="43.2" r=".46"/>
<circle cx="49.5" cy="43.2" r=".46"/>
<circle cx="47" cy="104.1" r=".46"/>
<circle cx="35.6" cy="104.1" r=".46"/>
<circle cx="54.6" cy="30.5" r=".46"/>
<circle cx="49.5" cy="33" r=".46"/>
<circle cx="45.7" cy="138.4" r=".46"/>
<circle cx="45.7" cy="146.1" r=".46"/>
<circle cx="66" cy="146.1" r=".46"/>
<circle cx="55.9" cy="146.1" r=".46"/>
<circle cx="35.6" cy="138.4" r=".46"/>
<circle cx="55.9" cy="138.4" r=".46"/>
<circle cx="35.6" cy="146.1" r=".46"/>
</g>
<use href="#words"/>
</svg>
